VERSION 5.7 ;
  NOWIREEXTENSIONATPIN ON ;
  DIVIDERCHAR "/" ;
  BUSBITCHARS "[]" ;
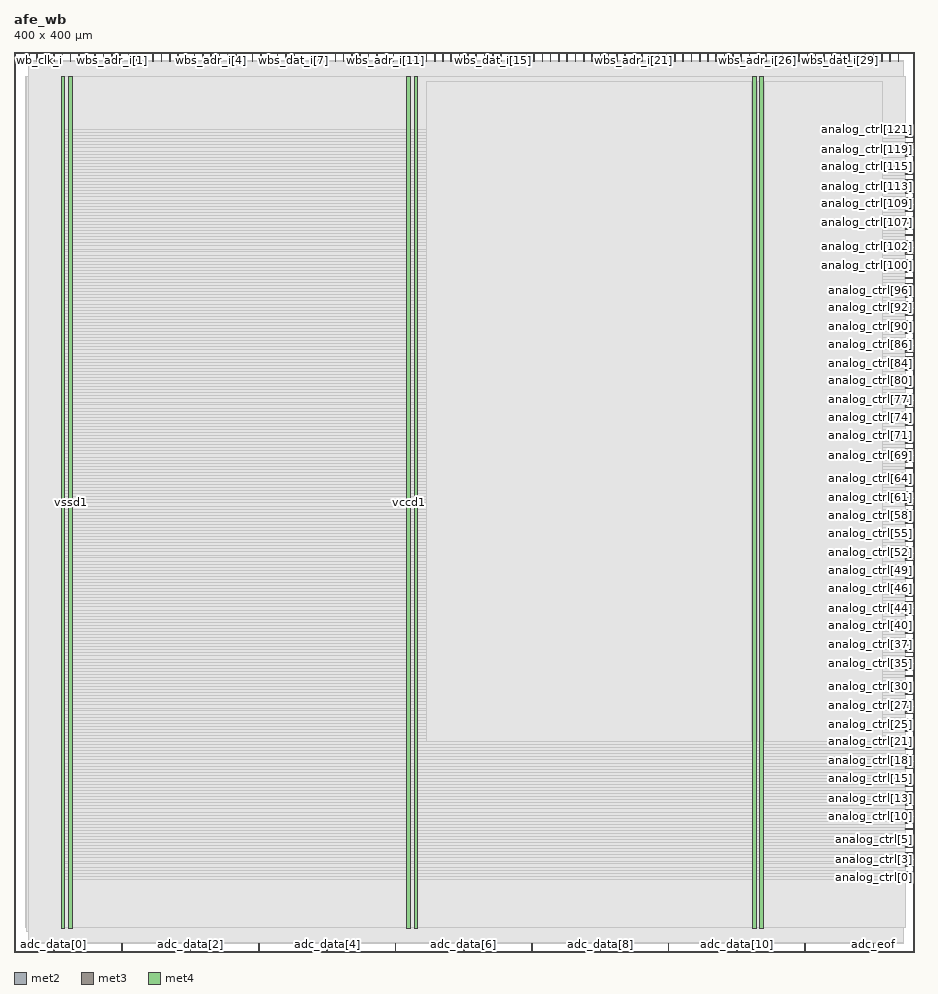
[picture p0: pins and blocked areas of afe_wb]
MACRO afe_wb
  CLASS BLOCK ;
  FOREIGN afe_wb ;
  ORIGIN 0.000 0.000 ;
  SIZE 400.000 BY 400.000 ;
  PIN adc_data[0]
    DIRECTION INPUT ;
    USE SIGNAL ;
    ANTENNAGATEAREA 0.213000 ;
    PORT
      LAYER met2 ;
        RECT 17.570 0.000 17.850 4.000 ;
    END
  END adc_data[0]
  PIN adc_data[10]
    DIRECTION INPUT ;
    USE SIGNAL ;
    ANTENNAGATEAREA 0.196500 ;
    PORT
      LAYER met2 ;
        RECT 321.170 0.000 321.450 4.000 ;
    END
  END adc_data[10]
  PIN adc_data[11]
    DIRECTION INPUT ;
    USE SIGNAL ;
    ANTENNAGATEAREA 0.126000 ;
    PORT
      LAYER met2 ;
        RECT 351.530 0.000 351.810 4.000 ;
    END
  END adc_data[11]
  PIN adc_data[1]
    DIRECTION INPUT ;
    USE SIGNAL ;
    ANTENNAGATEAREA 0.159000 ;
    PORT
      LAYER met2 ;
        RECT 47.930 0.000 48.210 4.000 ;
    END
  END adc_data[1]
  PIN adc_data[2]
    DIRECTION INPUT ;
    USE SIGNAL ;
    ANTENNAGATEAREA 0.213000 ;
    PORT
      LAYER met2 ;
        RECT 78.290 0.000 78.570 4.000 ;
    END
  END adc_data[2]
  PIN adc_data[3]
    DIRECTION INPUT ;
    USE SIGNAL ;
    ANTENNAGATEAREA 0.213000 ;
    PORT
      LAYER met2 ;
        RECT 108.650 0.000 108.930 4.000 ;
    END
  END adc_data[3]
  PIN adc_data[4]
    DIRECTION INPUT ;
    USE SIGNAL ;
    ANTENNAGATEAREA 0.213000 ;
    PORT
      LAYER met2 ;
        RECT 139.010 0.000 139.290 4.000 ;
    END
  END adc_data[4]
  PIN adc_data[5]
    DIRECTION INPUT ;
    USE SIGNAL ;
    ANTENNAGATEAREA 0.213000 ;
    PORT
      LAYER met2 ;
        RECT 169.370 0.000 169.650 4.000 ;
    END
  END adc_data[5]
  PIN adc_data[6]
    DIRECTION INPUT ;
    USE SIGNAL ;
    ANTENNAGATEAREA 0.213000 ;
    PORT
      LAYER met2 ;
        RECT 199.730 0.000 200.010 4.000 ;
    END
  END adc_data[6]
  PIN adc_data[7]
    DIRECTION INPUT ;
    USE SIGNAL ;
    ANTENNAGATEAREA 0.196500 ;
    PORT
      LAYER met2 ;
        RECT 230.090 0.000 230.370 4.000 ;
    END
  END adc_data[7]
  PIN adc_data[8]
    DIRECTION INPUT ;
    USE SIGNAL ;
    ANTENNAGATEAREA 0.196500 ;
    PORT
      LAYER met2 ;
        RECT 260.450 0.000 260.730 4.000 ;
    END
  END adc_data[8]
  PIN adc_data[9]
    DIRECTION INPUT ;
    USE SIGNAL ;
    ANTENNAGATEAREA 0.126000 ;
    PORT
      LAYER met2 ;
        RECT 290.810 0.000 291.090 4.000 ;
    END
  END adc_data[9]
  PIN adc_eof
    DIRECTION INPUT ;
    USE SIGNAL ;
    ANTENNAGATEAREA 0.213000 ;
    PORT
      LAYER met2 ;
        RECT 381.890 0.000 382.170 4.000 ;
    END
  END adc_eof
  PIN analog_ctrl[0]
    DIRECTION OUTPUT ;
    USE SIGNAL ;
    ANTENNADIFFAREA 2.673000 ;
    PORT
      LAYER met3 ;
        RECT 396.000 32.680 400.000 33.280 ;
    END
  END analog_ctrl[0]
  PIN analog_ctrl[100]
    DIRECTION OUTPUT ;
    USE SIGNAL ;
    PORT
      LAYER met3 ;
        RECT 396.000 304.680 400.000 305.280 ;
    END
  END analog_ctrl[100]
  PIN analog_ctrl[101]
    DIRECTION OUTPUT ;
    USE SIGNAL ;
    PORT
      LAYER met3 ;
        RECT 396.000 307.400 400.000 308.000 ;
    END
  END analog_ctrl[101]
  PIN analog_ctrl[102]
    DIRECTION OUTPUT ;
    USE SIGNAL ;
    PORT
      LAYER met3 ;
        RECT 396.000 310.120 400.000 310.720 ;
    END
  END analog_ctrl[102]
  PIN analog_ctrl[103]
    DIRECTION OUTPUT ;
    USE SIGNAL ;
    PORT
      LAYER met3 ;
        RECT 396.000 312.840 400.000 313.440 ;
    END
  END analog_ctrl[103]
  PIN analog_ctrl[104]
    DIRECTION OUTPUT ;
    USE SIGNAL ;
    ANTENNADIFFAREA 2.673000 ;
    PORT
      LAYER met3 ;
        RECT 396.000 315.560 400.000 316.160 ;
    END
  END analog_ctrl[104]
  PIN analog_ctrl[105]
    DIRECTION OUTPUT ;
    USE SIGNAL ;
    ANTENNADIFFAREA 2.673000 ;
    PORT
      LAYER met3 ;
        RECT 396.000 318.280 400.000 318.880 ;
    END
  END analog_ctrl[105]
  PIN analog_ctrl[106]
    DIRECTION OUTPUT ;
    USE SIGNAL ;
    ANTENNADIFFAREA 2.673000 ;
    PORT
      LAYER met3 ;
        RECT 396.000 321.000 400.000 321.600 ;
    END
  END analog_ctrl[106]
  PIN analog_ctrl[107]
    DIRECTION OUTPUT ;
    USE SIGNAL ;
    ANTENNADIFFAREA 2.673000 ;
    PORT
      LAYER met3 ;
        RECT 396.000 323.720 400.000 324.320 ;
    END
  END analog_ctrl[107]
  PIN analog_ctrl[108]
    DIRECTION OUTPUT ;
    USE SIGNAL ;
    ANTENNADIFFAREA 2.673000 ;
    PORT
      LAYER met3 ;
        RECT 396.000 326.440 400.000 327.040 ;
    END
  END analog_ctrl[108]
  PIN analog_ctrl[109]
    DIRECTION OUTPUT ;
    USE SIGNAL ;
    ANTENNADIFFAREA 2.673000 ;
    PORT
      LAYER met3 ;
        RECT 396.000 329.160 400.000 329.760 ;
    END
  END analog_ctrl[109]
  PIN analog_ctrl[10]
    DIRECTION OUTPUT ;
    USE SIGNAL ;
    ANTENNADIFFAREA 2.673000 ;
    PORT
      LAYER met3 ;
        RECT 396.000 59.880 400.000 60.480 ;
    END
  END analog_ctrl[10]
  PIN analog_ctrl[110]
    DIRECTION OUTPUT ;
    USE SIGNAL ;
    ANTENNADIFFAREA 2.673000 ;
    PORT
      LAYER met3 ;
        RECT 396.000 331.880 400.000 332.480 ;
    END
  END analog_ctrl[110]
  PIN analog_ctrl[111]
    DIRECTION OUTPUT ;
    USE SIGNAL ;
    ANTENNADIFFAREA 2.673000 ;
    PORT
      LAYER met3 ;
        RECT 396.000 334.600 400.000 335.200 ;
    END
  END analog_ctrl[111]
  PIN analog_ctrl[112]
    DIRECTION OUTPUT ;
    USE SIGNAL ;
    ANTENNADIFFAREA 2.673000 ;
    PORT
      LAYER met3 ;
        RECT 396.000 337.320 400.000 337.920 ;
    END
  END analog_ctrl[112]
  PIN analog_ctrl[113]
    DIRECTION OUTPUT ;
    USE SIGNAL ;
    ANTENNADIFFAREA 2.673000 ;
    PORT
      LAYER met3 ;
        RECT 396.000 340.040 400.000 340.640 ;
    END
  END analog_ctrl[113]
  PIN analog_ctrl[114]
    DIRECTION OUTPUT ;
    USE SIGNAL ;
    ANTENNADIFFAREA 2.673000 ;
    PORT
      LAYER met3 ;
        RECT 396.000 342.760 400.000 343.360 ;
    END
  END analog_ctrl[114]
  PIN analog_ctrl[115]
    DIRECTION OUTPUT ;
    USE SIGNAL ;
    ANTENNADIFFAREA 2.673000 ;
    PORT
      LAYER met3 ;
        RECT 396.000 345.480 400.000 346.080 ;
    END
  END analog_ctrl[115]
  PIN analog_ctrl[116]
    DIRECTION OUTPUT ;
    USE SIGNAL ;
    ANTENNADIFFAREA 2.673000 ;
    PORT
      LAYER met3 ;
        RECT 396.000 348.200 400.000 348.800 ;
    END
  END analog_ctrl[116]
  PIN analog_ctrl[117]
    DIRECTION OUTPUT ;
    USE SIGNAL ;
    ANTENNADIFFAREA 2.673000 ;
    PORT
      LAYER met3 ;
        RECT 396.000 350.920 400.000 351.520 ;
    END
  END analog_ctrl[117]
  PIN analog_ctrl[118]
    DIRECTION OUTPUT ;
    USE SIGNAL ;
    ANTENNADIFFAREA 2.673000 ;
    PORT
      LAYER met3 ;
        RECT 396.000 353.640 400.000 354.240 ;
    END
  END analog_ctrl[118]
  PIN analog_ctrl[119]
    DIRECTION OUTPUT ;
    USE SIGNAL ;
    ANTENNADIFFAREA 2.673000 ;
    PORT
      LAYER met3 ;
        RECT 396.000 356.360 400.000 356.960 ;
    END
  END analog_ctrl[119]
  PIN analog_ctrl[11]
    DIRECTION OUTPUT ;
    USE SIGNAL ;
    ANTENNADIFFAREA 2.673000 ;
    PORT
      LAYER met3 ;
        RECT 396.000 62.600 400.000 63.200 ;
    END
  END analog_ctrl[11]
  PIN analog_ctrl[120]
    DIRECTION OUTPUT ;
    USE SIGNAL ;
    ANTENNADIFFAREA 2.673000 ;
    PORT
      LAYER met3 ;
        RECT 396.000 359.080 400.000 359.680 ;
    END
  END analog_ctrl[120]
  PIN analog_ctrl[121]
    DIRECTION OUTPUT ;
    USE SIGNAL ;
    ANTENNADIFFAREA 2.673000 ;
    PORT
      LAYER met3 ;
        RECT 396.000 361.800 400.000 362.400 ;
    END
  END analog_ctrl[121]
  PIN analog_ctrl[122]
    DIRECTION OUTPUT ;
    USE SIGNAL ;
    ANTENNADIFFAREA 2.673000 ;
    PORT
      LAYER met3 ;
        RECT 396.000 364.520 400.000 365.120 ;
    END
  END analog_ctrl[122]
  PIN analog_ctrl[12]
    DIRECTION OUTPUT ;
    USE SIGNAL ;
    ANTENNADIFFAREA 2.673000 ;
    PORT
      LAYER met3 ;
        RECT 396.000 65.320 400.000 65.920 ;
    END
  END analog_ctrl[12]
  PIN analog_ctrl[13]
    DIRECTION OUTPUT ;
    USE SIGNAL ;
    ANTENNADIFFAREA 2.673000 ;
    PORT
      LAYER met3 ;
        RECT 396.000 68.040 400.000 68.640 ;
    END
  END analog_ctrl[13]
  PIN analog_ctrl[14]
    DIRECTION OUTPUT ;
    USE SIGNAL ;
    ANTENNADIFFAREA 2.673000 ;
    PORT
      LAYER met3 ;
        RECT 396.000 70.760 400.000 71.360 ;
    END
  END analog_ctrl[14]
  PIN analog_ctrl[15]
    DIRECTION OUTPUT ;
    USE SIGNAL ;
    ANTENNADIFFAREA 2.673000 ;
    PORT
      LAYER met3 ;
        RECT 396.000 73.480 400.000 74.080 ;
    END
  END analog_ctrl[15]
  PIN analog_ctrl[16]
    DIRECTION OUTPUT ;
    USE SIGNAL ;
    ANTENNADIFFAREA 2.673000 ;
    PORT
      LAYER met3 ;
        RECT 396.000 76.200 400.000 76.800 ;
    END
  END analog_ctrl[16]
  PIN analog_ctrl[17]
    DIRECTION OUTPUT ;
    USE SIGNAL ;
    ANTENNADIFFAREA 2.673000 ;
    PORT
      LAYER met3 ;
        RECT 396.000 78.920 400.000 79.520 ;
    END
  END analog_ctrl[17]
  PIN analog_ctrl[18]
    DIRECTION OUTPUT ;
    USE SIGNAL ;
    ANTENNADIFFAREA 2.673000 ;
    PORT
      LAYER met3 ;
        RECT 396.000 81.640 400.000 82.240 ;
    END
  END analog_ctrl[18]
  PIN analog_ctrl[19]
    DIRECTION OUTPUT ;
    USE SIGNAL ;
    ANTENNADIFFAREA 2.673000 ;
    PORT
      LAYER met3 ;
        RECT 396.000 84.360 400.000 84.960 ;
    END
  END analog_ctrl[19]
  PIN analog_ctrl[1]
    DIRECTION OUTPUT ;
    USE SIGNAL ;
    ANTENNADIFFAREA 2.673000 ;
    PORT
      LAYER met3 ;
        RECT 396.000 35.400 400.000 36.000 ;
    END
  END analog_ctrl[1]
  PIN analog_ctrl[20]
    DIRECTION OUTPUT ;
    USE SIGNAL ;
    ANTENNADIFFAREA 2.673000 ;
    PORT
      LAYER met3 ;
        RECT 396.000 87.080 400.000 87.680 ;
    END
  END analog_ctrl[20]
  PIN analog_ctrl[21]
    DIRECTION OUTPUT ;
    USE SIGNAL ;
    ANTENNADIFFAREA 2.673000 ;
    PORT
      LAYER met3 ;
        RECT 396.000 89.800 400.000 90.400 ;
    END
  END analog_ctrl[21]
  PIN analog_ctrl[22]
    DIRECTION OUTPUT ;
    USE SIGNAL ;
    ANTENNADIFFAREA 2.673000 ;
    PORT
      LAYER met3 ;
        RECT 396.000 92.520 400.000 93.120 ;
    END
  END analog_ctrl[22]
  PIN analog_ctrl[23]
    DIRECTION OUTPUT ;
    USE SIGNAL ;
    ANTENNADIFFAREA 2.673000 ;
    PORT
      LAYER met3 ;
        RECT 396.000 95.240 400.000 95.840 ;
    END
  END analog_ctrl[23]
  PIN analog_ctrl[24]
    DIRECTION OUTPUT ;
    USE SIGNAL ;
    ANTENNADIFFAREA 2.673000 ;
    PORT
      LAYER met3 ;
        RECT 396.000 97.960 400.000 98.560 ;
    END
  END analog_ctrl[24]
  PIN analog_ctrl[25]
    DIRECTION OUTPUT ;
    USE SIGNAL ;
    ANTENNADIFFAREA 2.673000 ;
    PORT
      LAYER met3 ;
        RECT 396.000 100.680 400.000 101.280 ;
    END
  END analog_ctrl[25]
  PIN analog_ctrl[26]
    DIRECTION OUTPUT ;
    USE SIGNAL ;
    ANTENNADIFFAREA 2.673000 ;
    PORT
      LAYER met3 ;
        RECT 396.000 103.400 400.000 104.000 ;
    END
  END analog_ctrl[26]
  PIN analog_ctrl[27]
    DIRECTION OUTPUT ;
    USE SIGNAL ;
    ANTENNADIFFAREA 2.673000 ;
    PORT
      LAYER met3 ;
        RECT 396.000 106.120 400.000 106.720 ;
    END
  END analog_ctrl[27]
  PIN analog_ctrl[28]
    DIRECTION OUTPUT ;
    USE SIGNAL ;
    ANTENNADIFFAREA 2.673000 ;
    PORT
      LAYER met3 ;
        RECT 396.000 108.840 400.000 109.440 ;
    END
  END analog_ctrl[28]
  PIN analog_ctrl[29]
    DIRECTION OUTPUT ;
    USE SIGNAL ;
    ANTENNADIFFAREA 2.673000 ;
    PORT
      LAYER met3 ;
        RECT 396.000 111.560 400.000 112.160 ;
    END
  END analog_ctrl[29]
  PIN analog_ctrl[2]
    DIRECTION OUTPUT ;
    USE SIGNAL ;
    ANTENNADIFFAREA 2.673000 ;
    PORT
      LAYER met3 ;
        RECT 396.000 38.120 400.000 38.720 ;
    END
  END analog_ctrl[2]
  PIN analog_ctrl[30]
    DIRECTION OUTPUT ;
    USE SIGNAL ;
    ANTENNADIFFAREA 2.673000 ;
    PORT
      LAYER met3 ;
        RECT 396.000 114.280 400.000 114.880 ;
    END
  END analog_ctrl[30]
  PIN analog_ctrl[31]
    DIRECTION OUTPUT ;
    USE SIGNAL ;
    ANTENNADIFFAREA 2.673000 ;
    PORT
      LAYER met3 ;
        RECT 396.000 117.000 400.000 117.600 ;
    END
  END analog_ctrl[31]
  PIN analog_ctrl[32]
    DIRECTION OUTPUT ;
    USE SIGNAL ;
    ANTENNADIFFAREA 2.673000 ;
    PORT
      LAYER met3 ;
        RECT 396.000 119.720 400.000 120.320 ;
    END
  END analog_ctrl[32]
  PIN analog_ctrl[33]
    DIRECTION OUTPUT ;
    USE SIGNAL ;
    ANTENNADIFFAREA 2.673000 ;
    PORT
      LAYER met3 ;
        RECT 396.000 122.440 400.000 123.040 ;
    END
  END analog_ctrl[33]
  PIN analog_ctrl[34]
    DIRECTION OUTPUT ;
    USE SIGNAL ;
    ANTENNADIFFAREA 2.673000 ;
    PORT
      LAYER met3 ;
        RECT 396.000 125.160 400.000 125.760 ;
    END
  END analog_ctrl[34]
  PIN analog_ctrl[35]
    DIRECTION OUTPUT ;
    USE SIGNAL ;
    ANTENNADIFFAREA 2.673000 ;
    PORT
      LAYER met3 ;
        RECT 396.000 127.880 400.000 128.480 ;
    END
  END analog_ctrl[35]
  PIN analog_ctrl[36]
    DIRECTION OUTPUT ;
    USE SIGNAL ;
    ANTENNADIFFAREA 2.673000 ;
    PORT
      LAYER met3 ;
        RECT 396.000 130.600 400.000 131.200 ;
    END
  END analog_ctrl[36]
  PIN analog_ctrl[37]
    DIRECTION OUTPUT ;
    USE SIGNAL ;
    ANTENNADIFFAREA 2.673000 ;
    PORT
      LAYER met3 ;
        RECT 396.000 133.320 400.000 133.920 ;
    END
  END analog_ctrl[37]
  PIN analog_ctrl[38]
    DIRECTION OUTPUT ;
    USE SIGNAL ;
    ANTENNADIFFAREA 2.673000 ;
    PORT
      LAYER met3 ;
        RECT 396.000 136.040 400.000 136.640 ;
    END
  END analog_ctrl[38]
  PIN analog_ctrl[39]
    DIRECTION OUTPUT ;
    USE SIGNAL ;
    ANTENNADIFFAREA 2.673000 ;
    PORT
      LAYER met3 ;
        RECT 396.000 138.760 400.000 139.360 ;
    END
  END analog_ctrl[39]
  PIN analog_ctrl[3]
    DIRECTION OUTPUT ;
    USE SIGNAL ;
    ANTENNADIFFAREA 2.673000 ;
    PORT
      LAYER met3 ;
        RECT 396.000 40.840 400.000 41.440 ;
    END
  END analog_ctrl[3]
  PIN analog_ctrl[40]
    DIRECTION OUTPUT ;
    USE SIGNAL ;
    ANTENNADIFFAREA 2.673000 ;
    PORT
      LAYER met3 ;
        RECT 396.000 141.480 400.000 142.080 ;
    END
  END analog_ctrl[40]
  PIN analog_ctrl[41]
    DIRECTION OUTPUT ;
    USE SIGNAL ;
    ANTENNADIFFAREA 2.673000 ;
    PORT
      LAYER met3 ;
        RECT 396.000 144.200 400.000 144.800 ;
    END
  END analog_ctrl[41]
  PIN analog_ctrl[42]
    DIRECTION OUTPUT ;
    USE SIGNAL ;
    ANTENNADIFFAREA 2.673000 ;
    PORT
      LAYER met3 ;
        RECT 396.000 146.920 400.000 147.520 ;
    END
  END analog_ctrl[42]
  PIN analog_ctrl[43]
    DIRECTION OUTPUT ;
    USE SIGNAL ;
    ANTENNADIFFAREA 2.673000 ;
    PORT
      LAYER met3 ;
        RECT 396.000 149.640 400.000 150.240 ;
    END
  END analog_ctrl[43]
  PIN analog_ctrl[44]
    DIRECTION OUTPUT ;
    USE SIGNAL ;
    ANTENNADIFFAREA 2.673000 ;
    PORT
      LAYER met3 ;
        RECT 396.000 152.360 400.000 152.960 ;
    END
  END analog_ctrl[44]
  PIN analog_ctrl[45]
    DIRECTION OUTPUT ;
    USE SIGNAL ;
    ANTENNADIFFAREA 2.673000 ;
    PORT
      LAYER met3 ;
        RECT 396.000 155.080 400.000 155.680 ;
    END
  END analog_ctrl[45]
  PIN analog_ctrl[46]
    DIRECTION OUTPUT ;
    USE SIGNAL ;
    ANTENNADIFFAREA 2.673000 ;
    PORT
      LAYER met3 ;
        RECT 396.000 157.800 400.000 158.400 ;
    END
  END analog_ctrl[46]
  PIN analog_ctrl[47]
    DIRECTION OUTPUT ;
    USE SIGNAL ;
    ANTENNADIFFAREA 2.673000 ;
    PORT
      LAYER met3 ;
        RECT 396.000 160.520 400.000 161.120 ;
    END
  END analog_ctrl[47]
  PIN analog_ctrl[48]
    DIRECTION OUTPUT ;
    USE SIGNAL ;
    ANTENNADIFFAREA 2.673000 ;
    PORT
      LAYER met3 ;
        RECT 396.000 163.240 400.000 163.840 ;
    END
  END analog_ctrl[48]
  PIN analog_ctrl[49]
    DIRECTION OUTPUT ;
    USE SIGNAL ;
    ANTENNADIFFAREA 2.673000 ;
    PORT
      LAYER met3 ;
        RECT 396.000 165.960 400.000 166.560 ;
    END
  END analog_ctrl[49]
  PIN analog_ctrl[4]
    DIRECTION OUTPUT ;
    USE SIGNAL ;
    ANTENNADIFFAREA 2.673000 ;
    PORT
      LAYER met3 ;
        RECT 396.000 43.560 400.000 44.160 ;
    END
  END analog_ctrl[4]
  PIN analog_ctrl[50]
    DIRECTION OUTPUT ;
    USE SIGNAL ;
    ANTENNADIFFAREA 2.673000 ;
    PORT
      LAYER met3 ;
        RECT 396.000 168.680 400.000 169.280 ;
    END
  END analog_ctrl[50]
  PIN analog_ctrl[51]
    DIRECTION OUTPUT ;
    USE SIGNAL ;
    ANTENNADIFFAREA 2.673000 ;
    PORT
      LAYER met3 ;
        RECT 396.000 171.400 400.000 172.000 ;
    END
  END analog_ctrl[51]
  PIN analog_ctrl[52]
    DIRECTION OUTPUT ;
    USE SIGNAL ;
    ANTENNADIFFAREA 2.673000 ;
    PORT
      LAYER met3 ;
        RECT 396.000 174.120 400.000 174.720 ;
    END
  END analog_ctrl[52]
  PIN analog_ctrl[53]
    DIRECTION OUTPUT ;
    USE SIGNAL ;
    ANTENNADIFFAREA 2.673000 ;
    PORT
      LAYER met3 ;
        RECT 396.000 176.840 400.000 177.440 ;
    END
  END analog_ctrl[53]
  PIN analog_ctrl[54]
    DIRECTION OUTPUT ;
    USE SIGNAL ;
    ANTENNADIFFAREA 2.673000 ;
    PORT
      LAYER met3 ;
        RECT 396.000 179.560 400.000 180.160 ;
    END
  END analog_ctrl[54]
  PIN analog_ctrl[55]
    DIRECTION OUTPUT ;
    USE SIGNAL ;
    ANTENNADIFFAREA 2.673000 ;
    PORT
      LAYER met3 ;
        RECT 396.000 182.280 400.000 182.880 ;
    END
  END analog_ctrl[55]
  PIN analog_ctrl[56]
    DIRECTION OUTPUT ;
    USE SIGNAL ;
    ANTENNADIFFAREA 2.673000 ;
    PORT
      LAYER met3 ;
        RECT 396.000 185.000 400.000 185.600 ;
    END
  END analog_ctrl[56]
  PIN analog_ctrl[57]
    DIRECTION OUTPUT ;
    USE SIGNAL ;
    ANTENNADIFFAREA 2.673000 ;
    PORT
      LAYER met3 ;
        RECT 396.000 187.720 400.000 188.320 ;
    END
  END analog_ctrl[57]
  PIN analog_ctrl[58]
    DIRECTION OUTPUT ;
    USE SIGNAL ;
    ANTENNADIFFAREA 2.673000 ;
    PORT
      LAYER met3 ;
        RECT 396.000 190.440 400.000 191.040 ;
    END
  END analog_ctrl[58]
  PIN analog_ctrl[59]
    DIRECTION OUTPUT ;
    USE SIGNAL ;
    ANTENNADIFFAREA 2.673000 ;
    PORT
      LAYER met3 ;
        RECT 396.000 193.160 400.000 193.760 ;
    END
  END analog_ctrl[59]
  PIN analog_ctrl[5]
    DIRECTION OUTPUT ;
    USE SIGNAL ;
    ANTENNADIFFAREA 2.673000 ;
    PORT
      LAYER met3 ;
        RECT 396.000 46.280 400.000 46.880 ;
    END
  END analog_ctrl[5]
  PIN analog_ctrl[60]
    DIRECTION OUTPUT ;
    USE SIGNAL ;
    ANTENNADIFFAREA 2.673000 ;
    PORT
      LAYER met3 ;
        RECT 396.000 195.880 400.000 196.480 ;
    END
  END analog_ctrl[60]
  PIN analog_ctrl[61]
    DIRECTION OUTPUT ;
    USE SIGNAL ;
    ANTENNADIFFAREA 2.673000 ;
    PORT
      LAYER met3 ;
        RECT 396.000 198.600 400.000 199.200 ;
    END
  END analog_ctrl[61]
  PIN analog_ctrl[62]
    DIRECTION OUTPUT ;
    USE SIGNAL ;
    ANTENNADIFFAREA 2.673000 ;
    PORT
      LAYER met3 ;
        RECT 396.000 201.320 400.000 201.920 ;
    END
  END analog_ctrl[62]
  PIN analog_ctrl[63]
    DIRECTION OUTPUT ;
    USE SIGNAL ;
    ANTENNADIFFAREA 2.673000 ;
    PORT
      LAYER met3 ;
        RECT 396.000 204.040 400.000 204.640 ;
    END
  END analog_ctrl[63]
  PIN analog_ctrl[64]
    DIRECTION OUTPUT ;
    USE SIGNAL ;
    ANTENNADIFFAREA 2.673000 ;
    PORT
      LAYER met3 ;
        RECT 396.000 206.760 400.000 207.360 ;
    END
  END analog_ctrl[64]
  PIN analog_ctrl[65]
    DIRECTION OUTPUT ;
    USE SIGNAL ;
    ANTENNADIFFAREA 2.673000 ;
    PORT
      LAYER met3 ;
        RECT 396.000 209.480 400.000 210.080 ;
    END
  END analog_ctrl[65]
  PIN analog_ctrl[66]
    DIRECTION OUTPUT ;
    USE SIGNAL ;
    ANTENNADIFFAREA 2.673000 ;
    PORT
      LAYER met3 ;
        RECT 396.000 212.200 400.000 212.800 ;
    END
  END analog_ctrl[66]
  PIN analog_ctrl[67]
    DIRECTION OUTPUT ;
    USE SIGNAL ;
    ANTENNADIFFAREA 2.673000 ;
    PORT
      LAYER met3 ;
        RECT 396.000 214.920 400.000 215.520 ;
    END
  END analog_ctrl[67]
  PIN analog_ctrl[68]
    DIRECTION OUTPUT ;
    USE SIGNAL ;
    ANTENNADIFFAREA 2.673000 ;
    PORT
      LAYER met3 ;
        RECT 396.000 217.640 400.000 218.240 ;
    END
  END analog_ctrl[68]
  PIN analog_ctrl[69]
    DIRECTION OUTPUT ;
    USE SIGNAL ;
    ANTENNADIFFAREA 2.673000 ;
    PORT
      LAYER met3 ;
        RECT 396.000 220.360 400.000 220.960 ;
    END
  END analog_ctrl[69]
  PIN analog_ctrl[6]
    DIRECTION OUTPUT ;
    USE SIGNAL ;
    ANTENNADIFFAREA 2.673000 ;
    PORT
      LAYER met3 ;
        RECT 396.000 49.000 400.000 49.600 ;
    END
  END analog_ctrl[6]
  PIN analog_ctrl[70]
    DIRECTION OUTPUT ;
    USE SIGNAL ;
    ANTENNADIFFAREA 2.673000 ;
    PORT
      LAYER met3 ;
        RECT 396.000 223.080 400.000 223.680 ;
    END
  END analog_ctrl[70]
  PIN analog_ctrl[71]
    DIRECTION OUTPUT ;
    USE SIGNAL ;
    ANTENNADIFFAREA 2.673000 ;
    PORT
      LAYER met3 ;
        RECT 396.000 225.800 400.000 226.400 ;
    END
  END analog_ctrl[71]
  PIN analog_ctrl[72]
    DIRECTION OUTPUT ;
    USE SIGNAL ;
    ANTENNADIFFAREA 2.673000 ;
    PORT
      LAYER met3 ;
        RECT 396.000 228.520 400.000 229.120 ;
    END
  END analog_ctrl[72]
  PIN analog_ctrl[73]
    DIRECTION OUTPUT ;
    USE SIGNAL ;
    ANTENNADIFFAREA 2.673000 ;
    PORT
      LAYER met3 ;
        RECT 396.000 231.240 400.000 231.840 ;
    END
  END analog_ctrl[73]
  PIN analog_ctrl[74]
    DIRECTION OUTPUT ;
    USE SIGNAL ;
    ANTENNADIFFAREA 2.673000 ;
    PORT
      LAYER met3 ;
        RECT 396.000 233.960 400.000 234.560 ;
    END
  END analog_ctrl[74]
  PIN analog_ctrl[75]
    DIRECTION OUTPUT ;
    USE SIGNAL ;
    ANTENNADIFFAREA 2.673000 ;
    PORT
      LAYER met3 ;
        RECT 396.000 236.680 400.000 237.280 ;
    END
  END analog_ctrl[75]
  PIN analog_ctrl[76]
    DIRECTION OUTPUT ;
    USE SIGNAL ;
    ANTENNADIFFAREA 2.673000 ;
    PORT
      LAYER met3 ;
        RECT 396.000 239.400 400.000 240.000 ;
    END
  END analog_ctrl[76]
  PIN analog_ctrl[77]
    DIRECTION OUTPUT ;
    USE SIGNAL ;
    ANTENNADIFFAREA 2.673000 ;
    PORT
      LAYER met3 ;
        RECT 396.000 242.120 400.000 242.720 ;
    END
  END analog_ctrl[77]
  PIN analog_ctrl[78]
    DIRECTION OUTPUT ;
    USE SIGNAL ;
    ANTENNADIFFAREA 2.673000 ;
    PORT
      LAYER met3 ;
        RECT 396.000 244.840 400.000 245.440 ;
    END
  END analog_ctrl[78]
  PIN analog_ctrl[79]
    DIRECTION OUTPUT ;
    USE SIGNAL ;
    ANTENNADIFFAREA 2.673000 ;
    PORT
      LAYER met3 ;
        RECT 396.000 247.560 400.000 248.160 ;
    END
  END analog_ctrl[79]
  PIN analog_ctrl[7]
    DIRECTION OUTPUT ;
    USE SIGNAL ;
    PORT
      LAYER met3 ;
        RECT 396.000 51.720 400.000 52.320 ;
    END
  END analog_ctrl[7]
  PIN analog_ctrl[80]
    DIRECTION OUTPUT ;
    USE SIGNAL ;
    ANTENNADIFFAREA 2.673000 ;
    PORT
      LAYER met3 ;
        RECT 396.000 250.280 400.000 250.880 ;
    END
  END analog_ctrl[80]
  PIN analog_ctrl[81]
    DIRECTION OUTPUT ;
    USE SIGNAL ;
    ANTENNADIFFAREA 2.673000 ;
    PORT
      LAYER met3 ;
        RECT 396.000 253.000 400.000 253.600 ;
    END
  END analog_ctrl[81]
  PIN analog_ctrl[82]
    DIRECTION OUTPUT ;
    USE SIGNAL ;
    ANTENNADIFFAREA 2.673000 ;
    PORT
      LAYER met3 ;
        RECT 396.000 255.720 400.000 256.320 ;
    END
  END analog_ctrl[82]
  PIN analog_ctrl[83]
    DIRECTION OUTPUT ;
    USE SIGNAL ;
    ANTENNADIFFAREA 2.673000 ;
    PORT
      LAYER met3 ;
        RECT 396.000 258.440 400.000 259.040 ;
    END
  END analog_ctrl[83]
  PIN analog_ctrl[84]
    DIRECTION OUTPUT ;
    USE SIGNAL ;
    ANTENNADIFFAREA 2.673000 ;
    PORT
      LAYER met3 ;
        RECT 396.000 261.160 400.000 261.760 ;
    END
  END analog_ctrl[84]
  PIN analog_ctrl[85]
    DIRECTION OUTPUT ;
    USE SIGNAL ;
    ANTENNADIFFAREA 2.673000 ;
    PORT
      LAYER met3 ;
        RECT 396.000 263.880 400.000 264.480 ;
    END
  END analog_ctrl[85]
  PIN analog_ctrl[86]
    DIRECTION OUTPUT ;
    USE SIGNAL ;
    ANTENNADIFFAREA 2.673000 ;
    PORT
      LAYER met3 ;
        RECT 396.000 266.600 400.000 267.200 ;
    END
  END analog_ctrl[86]
  PIN analog_ctrl[87]
    DIRECTION OUTPUT ;
    USE SIGNAL ;
    ANTENNADIFFAREA 2.673000 ;
    PORT
      LAYER met3 ;
        RECT 396.000 269.320 400.000 269.920 ;
    END
  END analog_ctrl[87]
  PIN analog_ctrl[88]
    DIRECTION OUTPUT ;
    USE SIGNAL ;
    ANTENNADIFFAREA 2.673000 ;
    PORT
      LAYER met3 ;
        RECT 396.000 272.040 400.000 272.640 ;
    END
  END analog_ctrl[88]
  PIN analog_ctrl[89]
    DIRECTION OUTPUT ;
    USE SIGNAL ;
    ANTENNADIFFAREA 2.673000 ;
    PORT
      LAYER met3 ;
        RECT 396.000 274.760 400.000 275.360 ;
    END
  END analog_ctrl[89]
  PIN analog_ctrl[8]
    DIRECTION OUTPUT ;
    USE SIGNAL ;
    ANTENNADIFFAREA 2.673000 ;
    PORT
      LAYER met3 ;
        RECT 396.000 54.440 400.000 55.040 ;
    END
  END analog_ctrl[8]
  PIN analog_ctrl[90]
    DIRECTION OUTPUT ;
    USE SIGNAL ;
    ANTENNADIFFAREA 2.673000 ;
    PORT
      LAYER met3 ;
        RECT 396.000 277.480 400.000 278.080 ;
    END
  END analog_ctrl[90]
  PIN analog_ctrl[91]
    DIRECTION OUTPUT ;
    USE SIGNAL ;
    ANTENNADIFFAREA 2.673000 ;
    PORT
      LAYER met3 ;
        RECT 396.000 280.200 400.000 280.800 ;
    END
  END analog_ctrl[91]
  PIN analog_ctrl[92]
    DIRECTION OUTPUT ;
    USE SIGNAL ;
    ANTENNADIFFAREA 2.673000 ;
    PORT
      LAYER met3 ;
        RECT 396.000 282.920 400.000 283.520 ;
    END
  END analog_ctrl[92]
  PIN analog_ctrl[93]
    DIRECTION OUTPUT ;
    USE SIGNAL ;
    ANTENNADIFFAREA 2.673000 ;
    PORT
      LAYER met3 ;
        RECT 396.000 285.640 400.000 286.240 ;
    END
  END analog_ctrl[93]
  PIN analog_ctrl[94]
    DIRECTION OUTPUT ;
    USE SIGNAL ;
    ANTENNADIFFAREA 2.673000 ;
    PORT
      LAYER met3 ;
        RECT 396.000 288.360 400.000 288.960 ;
    END
  END analog_ctrl[94]
  PIN analog_ctrl[95]
    DIRECTION OUTPUT ;
    USE SIGNAL ;
    ANTENNADIFFAREA 2.673000 ;
    PORT
      LAYER met3 ;
        RECT 396.000 291.080 400.000 291.680 ;
    END
  END analog_ctrl[95]
  PIN analog_ctrl[96]
    DIRECTION OUTPUT ;
    USE SIGNAL ;
    ANTENNADIFFAREA 2.673000 ;
    PORT
      LAYER met3 ;
        RECT 396.000 293.800 400.000 294.400 ;
    END
  END analog_ctrl[96]
  PIN analog_ctrl[97]
    DIRECTION OUTPUT ;
    USE SIGNAL ;
    ANTENNADIFFAREA 2.673000 ;
    PORT
      LAYER met3 ;
        RECT 396.000 296.520 400.000 297.120 ;
    END
  END analog_ctrl[97]
  PIN analog_ctrl[98]
    DIRECTION OUTPUT ;
    USE SIGNAL ;
    PORT
      LAYER met3 ;
        RECT 396.000 299.240 400.000 299.840 ;
    END
  END analog_ctrl[98]
  PIN analog_ctrl[99]
    DIRECTION OUTPUT ;
    USE SIGNAL ;
    PORT
      LAYER met3 ;
        RECT 396.000 301.960 400.000 302.560 ;
    END
  END analog_ctrl[99]
  PIN analog_ctrl[9]
    DIRECTION OUTPUT ;
    USE SIGNAL ;
    ANTENNADIFFAREA 2.673000 ;
    PORT
      LAYER met3 ;
        RECT 396.000 57.160 400.000 57.760 ;
    END
  END analog_ctrl[9]
  PIN vccd1
    DIRECTION INOUT ;
    USE POWER ;
    PORT
      LAYER met4 ;
        RECT 21.040 10.640 22.640 389.200 ;
    END
    PORT
      LAYER met4 ;
        RECT 174.640 10.640 176.240 389.200 ;
    END
    PORT
      LAYER met4 ;
        RECT 328.240 10.640 329.840 389.200 ;
    END
  END vccd1
  PIN vssd1
    DIRECTION INOUT ;
    USE GROUND ;
    PORT
      LAYER met4 ;
        RECT 24.340 10.640 25.940 389.200 ;
    END
    PORT
      LAYER met4 ;
        RECT 177.940 10.640 179.540 389.200 ;
    END
    PORT
      LAYER met4 ;
        RECT 331.540 10.640 333.140 389.200 ;
    END
  END vssd1
  PIN wb_clk_i
    DIRECTION INPUT ;
    USE SIGNAL ;
    ANTENNAGATEAREA 0.852000 ;
    PORT
      LAYER met2 ;
        RECT 6.530 396.000 6.810 400.000 ;
    END
  END wb_clk_i
  PIN wb_rst_i
    DIRECTION INPUT ;
    USE SIGNAL ;
    ANTENNAGATEAREA 0.126000 ;
    PORT
      LAYER met2 ;
        RECT 10.210 396.000 10.490 400.000 ;
    END
  END wb_rst_i
  PIN wbs_ack_o
    DIRECTION OUTPUT ;
    USE SIGNAL ;
    ANTENNADIFFAREA 2.673000 ;
    PORT
      LAYER met2 ;
        RECT 13.890 396.000 14.170 400.000 ;
    END
  END wbs_ack_o
  PIN wbs_adr_i[0]
    DIRECTION INPUT ;
    USE SIGNAL ;
    PORT
      LAYER met2 ;
        RECT 28.610 396.000 28.890 400.000 ;
    END
  END wbs_adr_i[0]
  PIN wbs_adr_i[10]
    DIRECTION INPUT ;
    USE SIGNAL ;
    PORT
      LAYER met2 ;
        RECT 153.730 396.000 154.010 400.000 ;
    END
  END wbs_adr_i[10]
  PIN wbs_adr_i[11]
    DIRECTION INPUT ;
    USE SIGNAL ;
    PORT
      LAYER met2 ;
        RECT 164.770 396.000 165.050 400.000 ;
    END
  END wbs_adr_i[11]
  PIN wbs_adr_i[12]
    DIRECTION INPUT ;
    USE SIGNAL ;
    PORT
      LAYER met2 ;
        RECT 175.810 396.000 176.090 400.000 ;
    END
  END wbs_adr_i[12]
  PIN wbs_adr_i[13]
    DIRECTION INPUT ;
    USE SIGNAL ;
    PORT
      LAYER met2 ;
        RECT 186.850 396.000 187.130 400.000 ;
    END
  END wbs_adr_i[13]
  PIN wbs_adr_i[14]
    DIRECTION INPUT ;
    USE SIGNAL ;
    PORT
      LAYER met2 ;
        RECT 197.890 396.000 198.170 400.000 ;
    END
  END wbs_adr_i[14]
  PIN wbs_adr_i[15]
    DIRECTION INPUT ;
    USE SIGNAL ;
    PORT
      LAYER met2 ;
        RECT 208.930 396.000 209.210 400.000 ;
    END
  END wbs_adr_i[15]
  PIN wbs_adr_i[16]
    DIRECTION INPUT ;
    USE SIGNAL ;
    PORT
      LAYER met2 ;
        RECT 219.970 396.000 220.250 400.000 ;
    END
  END wbs_adr_i[16]
  PIN wbs_adr_i[17]
    DIRECTION INPUT ;
    USE SIGNAL ;
    PORT
      LAYER met2 ;
        RECT 231.010 396.000 231.290 400.000 ;
    END
  END wbs_adr_i[17]
  PIN wbs_adr_i[18]
    DIRECTION INPUT ;
    USE SIGNAL ;
    PORT
      LAYER met2 ;
        RECT 242.050 396.000 242.330 400.000 ;
    END
  END wbs_adr_i[18]
  PIN wbs_adr_i[19]
    DIRECTION INPUT ;
    USE SIGNAL ;
    PORT
      LAYER met2 ;
        RECT 253.090 396.000 253.370 400.000 ;
    END
  END wbs_adr_i[19]
  PIN wbs_adr_i[1]
    DIRECTION INPUT ;
    USE SIGNAL ;
    PORT
      LAYER met2 ;
        RECT 43.330 396.000 43.610 400.000 ;
    END
  END wbs_adr_i[1]
  PIN wbs_adr_i[20]
    DIRECTION INPUT ;
    USE SIGNAL ;
    PORT
      LAYER met2 ;
        RECT 264.130 396.000 264.410 400.000 ;
    END
  END wbs_adr_i[20]
  PIN wbs_adr_i[21]
    DIRECTION INPUT ;
    USE SIGNAL ;
    PORT
      LAYER met2 ;
        RECT 275.170 396.000 275.450 400.000 ;
    END
  END wbs_adr_i[21]
  PIN wbs_adr_i[22]
    DIRECTION INPUT ;
    USE SIGNAL ;
    PORT
      LAYER met2 ;
        RECT 286.210 396.000 286.490 400.000 ;
    END
  END wbs_adr_i[22]
  PIN wbs_adr_i[23]
    DIRECTION INPUT ;
    USE SIGNAL ;
    PORT
      LAYER met2 ;
        RECT 297.250 396.000 297.530 400.000 ;
    END
  END wbs_adr_i[23]
  PIN wbs_adr_i[24]
    DIRECTION INPUT ;
    USE SIGNAL ;
    PORT
      LAYER met2 ;
        RECT 308.290 396.000 308.570 400.000 ;
    END
  END wbs_adr_i[24]
  PIN wbs_adr_i[25]
    DIRECTION INPUT ;
    USE SIGNAL ;
    PORT
      LAYER met2 ;
        RECT 319.330 396.000 319.610 400.000 ;
    END
  END wbs_adr_i[25]
  PIN wbs_adr_i[26]
    DIRECTION INPUT ;
    USE SIGNAL ;
    PORT
      LAYER met2 ;
        RECT 330.370 396.000 330.650 400.000 ;
    END
  END wbs_adr_i[26]
  PIN wbs_adr_i[27]
    DIRECTION INPUT ;
    USE SIGNAL ;
    PORT
      LAYER met2 ;
        RECT 341.410 396.000 341.690 400.000 ;
    END
  END wbs_adr_i[27]
  PIN wbs_adr_i[28]
    DIRECTION INPUT ;
    USE SIGNAL ;
    PORT
      LAYER met2 ;
        RECT 352.450 396.000 352.730 400.000 ;
    END
  END wbs_adr_i[28]
  PIN wbs_adr_i[29]
    DIRECTION INPUT ;
    USE SIGNAL ;
    PORT
      LAYER met2 ;
        RECT 363.490 396.000 363.770 400.000 ;
    END
  END wbs_adr_i[29]
  PIN wbs_adr_i[2]
    DIRECTION INPUT ;
    USE SIGNAL ;
    ANTENNAGATEAREA 0.126000 ;
    PORT
      LAYER met2 ;
        RECT 58.050 396.000 58.330 400.000 ;
    END
  END wbs_adr_i[2]
  PIN wbs_adr_i[30]
    DIRECTION INPUT ;
    USE SIGNAL ;
    PORT
      LAYER met2 ;
        RECT 374.530 396.000 374.810 400.000 ;
    END
  END wbs_adr_i[30]
  PIN wbs_adr_i[31]
    DIRECTION INPUT ;
    USE SIGNAL ;
    PORT
      LAYER met2 ;
        RECT 385.570 396.000 385.850 400.000 ;
    END
  END wbs_adr_i[31]
  PIN wbs_adr_i[3]
    DIRECTION INPUT ;
    USE SIGNAL ;
    ANTENNAGATEAREA 0.126000 ;
    PORT
      LAYER met2 ;
        RECT 72.770 396.000 73.050 400.000 ;
    END
  END wbs_adr_i[3]
  PIN wbs_adr_i[4]
    DIRECTION INPUT ;
    USE SIGNAL ;
    ANTENNAGATEAREA 0.126000 ;
    PORT
      LAYER met2 ;
        RECT 87.490 396.000 87.770 400.000 ;
    END
  END wbs_adr_i[4]
  PIN wbs_adr_i[5]
    DIRECTION INPUT ;
    USE SIGNAL ;
    ANTENNAGATEAREA 0.126000 ;
    PORT
      LAYER met2 ;
        RECT 98.530 396.000 98.810 400.000 ;
    END
  END wbs_adr_i[5]
  PIN wbs_adr_i[6]
    DIRECTION INPUT ;
    USE SIGNAL ;
    PORT
      LAYER met2 ;
        RECT 109.570 396.000 109.850 400.000 ;
    END
  END wbs_adr_i[6]
  PIN wbs_adr_i[7]
    DIRECTION INPUT ;
    USE SIGNAL ;
    PORT
      LAYER met2 ;
        RECT 120.610 396.000 120.890 400.000 ;
    END
  END wbs_adr_i[7]
  PIN wbs_adr_i[8]
    DIRECTION INPUT ;
    USE SIGNAL ;
    PORT
      LAYER met2 ;
        RECT 131.650 396.000 131.930 400.000 ;
    END
  END wbs_adr_i[8]
  PIN wbs_adr_i[9]
    DIRECTION INPUT ;
    USE SIGNAL ;
    PORT
      LAYER met2 ;
        RECT 142.690 396.000 142.970 400.000 ;
    END
  END wbs_adr_i[9]
  PIN wbs_cyc_i
    DIRECTION INPUT ;
    USE SIGNAL ;
    ANTENNAGATEAREA 0.213000 ;
    PORT
      LAYER met2 ;
        RECT 17.570 396.000 17.850 400.000 ;
    END
  END wbs_cyc_i
  PIN wbs_dat_i[0]
    DIRECTION INPUT ;
    USE SIGNAL ;
    ANTENNAGATEAREA 0.126000 ;
    PORT
      LAYER met2 ;
        RECT 32.290 396.000 32.570 400.000 ;
    END
  END wbs_dat_i[0]
  PIN wbs_dat_i[10]
    DIRECTION INPUT ;
    USE SIGNAL ;
    ANTENNAGATEAREA 0.126000 ;
    PORT
      LAYER met2 ;
        RECT 157.410 396.000 157.690 400.000 ;
    END
  END wbs_dat_i[10]
  PIN wbs_dat_i[11]
    DIRECTION INPUT ;
    USE SIGNAL ;
    ANTENNAGATEAREA 0.126000 ;
    PORT
      LAYER met2 ;
        RECT 168.450 396.000 168.730 400.000 ;
    END
  END wbs_dat_i[11]
  PIN wbs_dat_i[12]
    DIRECTION INPUT ;
    USE SIGNAL ;
    ANTENNAGATEAREA 0.126000 ;
    PORT
      LAYER met2 ;
        RECT 179.490 396.000 179.770 400.000 ;
    END
  END wbs_dat_i[12]
  PIN wbs_dat_i[13]
    DIRECTION INPUT ;
    USE SIGNAL ;
    ANTENNAGATEAREA 0.126000 ;
    PORT
      LAYER met2 ;
        RECT 190.530 396.000 190.810 400.000 ;
    END
  END wbs_dat_i[13]
  PIN wbs_dat_i[14]
    DIRECTION INPUT ;
    USE SIGNAL ;
    ANTENNAGATEAREA 0.126000 ;
    PORT
      LAYER met2 ;
        RECT 201.570 396.000 201.850 400.000 ;
    END
  END wbs_dat_i[14]
  PIN wbs_dat_i[15]
    DIRECTION INPUT ;
    USE SIGNAL ;
    ANTENNAGATEAREA 0.126000 ;
    PORT
      LAYER met2 ;
        RECT 212.610 396.000 212.890 400.000 ;
    END
  END wbs_dat_i[15]
  PIN wbs_dat_i[16]
    DIRECTION INPUT ;
    USE SIGNAL ;
    ANTENNAGATEAREA 0.126000 ;
    PORT
      LAYER met2 ;
        RECT 223.650 396.000 223.930 400.000 ;
    END
  END wbs_dat_i[16]
  PIN wbs_dat_i[17]
    DIRECTION INPUT ;
    USE SIGNAL ;
    ANTENNAGATEAREA 0.126000 ;
    PORT
      LAYER met2 ;
        RECT 234.690 396.000 234.970 400.000 ;
    END
  END wbs_dat_i[17]
  PIN wbs_dat_i[18]
    DIRECTION INPUT ;
    USE SIGNAL ;
    ANTENNAGATEAREA 0.126000 ;
    PORT
      LAYER met2 ;
        RECT 245.730 396.000 246.010 400.000 ;
    END
  END wbs_dat_i[18]
  PIN wbs_dat_i[19]
    DIRECTION INPUT ;
    USE SIGNAL ;
    ANTENNAGATEAREA 0.126000 ;
    PORT
      LAYER met2 ;
        RECT 256.770 396.000 257.050 400.000 ;
    END
  END wbs_dat_i[19]
  PIN wbs_dat_i[1]
    DIRECTION INPUT ;
    USE SIGNAL ;
    ANTENNAGATEAREA 0.126000 ;
    PORT
      LAYER met2 ;
        RECT 47.010 396.000 47.290 400.000 ;
    END
  END wbs_dat_i[1]
  PIN wbs_dat_i[20]
    DIRECTION INPUT ;
    USE SIGNAL ;
    ANTENNAGATEAREA 0.126000 ;
    PORT
      LAYER met2 ;
        RECT 267.810 396.000 268.090 400.000 ;
    END
  END wbs_dat_i[20]
  PIN wbs_dat_i[21]
    DIRECTION INPUT ;
    USE SIGNAL ;
    ANTENNAGATEAREA 0.126000 ;
    PORT
      LAYER met2 ;
        RECT 278.850 396.000 279.130 400.000 ;
    END
  END wbs_dat_i[21]
  PIN wbs_dat_i[22]
    DIRECTION INPUT ;
    USE SIGNAL ;
    ANTENNAGATEAREA 0.126000 ;
    PORT
      LAYER met2 ;
        RECT 289.890 396.000 290.170 400.000 ;
    END
  END wbs_dat_i[22]
  PIN wbs_dat_i[23]
    DIRECTION INPUT ;
    USE SIGNAL ;
    ANTENNAGATEAREA 0.126000 ;
    PORT
      LAYER met2 ;
        RECT 300.930 396.000 301.210 400.000 ;
    END
  END wbs_dat_i[23]
  PIN wbs_dat_i[24]
    DIRECTION INPUT ;
    USE SIGNAL ;
    ANTENNAGATEAREA 0.126000 ;
    PORT
      LAYER met2 ;
        RECT 311.970 396.000 312.250 400.000 ;
    END
  END wbs_dat_i[24]
  PIN wbs_dat_i[25]
    DIRECTION INPUT ;
    USE SIGNAL ;
    ANTENNAGATEAREA 0.126000 ;
    PORT
      LAYER met2 ;
        RECT 323.010 396.000 323.290 400.000 ;
    END
  END wbs_dat_i[25]
  PIN wbs_dat_i[26]
    DIRECTION INPUT ;
    USE SIGNAL ;
    ANTENNAGATEAREA 0.126000 ;
    PORT
      LAYER met2 ;
        RECT 334.050 396.000 334.330 400.000 ;
    END
  END wbs_dat_i[26]
  PIN wbs_dat_i[27]
    DIRECTION INPUT ;
    USE SIGNAL ;
    ANTENNAGATEAREA 0.126000 ;
    PORT
      LAYER met2 ;
        RECT 345.090 396.000 345.370 400.000 ;
    END
  END wbs_dat_i[27]
  PIN wbs_dat_i[28]
    DIRECTION INPUT ;
    USE SIGNAL ;
    ANTENNAGATEAREA 0.126000 ;
    PORT
      LAYER met2 ;
        RECT 356.130 396.000 356.410 400.000 ;
    END
  END wbs_dat_i[28]
  PIN wbs_dat_i[29]
    DIRECTION INPUT ;
    USE SIGNAL ;
    ANTENNAGATEAREA 0.126000 ;
    PORT
      LAYER met2 ;
        RECT 367.170 396.000 367.450 400.000 ;
    END
  END wbs_dat_i[29]
  PIN wbs_dat_i[2]
    DIRECTION INPUT ;
    USE SIGNAL ;
    ANTENNAGATEAREA 0.126000 ;
    PORT
      LAYER met2 ;
        RECT 61.730 396.000 62.010 400.000 ;
    END
  END wbs_dat_i[2]
  PIN wbs_dat_i[30]
    DIRECTION INPUT ;
    USE SIGNAL ;
    ANTENNAGATEAREA 0.126000 ;
    PORT
      LAYER met2 ;
        RECT 378.210 396.000 378.490 400.000 ;
    END
  END wbs_dat_i[30]
  PIN wbs_dat_i[31]
    DIRECTION INPUT ;
    USE SIGNAL ;
    ANTENNAGATEAREA 0.126000 ;
    PORT
      LAYER met2 ;
        RECT 389.250 396.000 389.530 400.000 ;
    END
  END wbs_dat_i[31]
  PIN wbs_dat_i[3]
    DIRECTION INPUT ;
    USE SIGNAL ;
    ANTENNAGATEAREA 0.126000 ;
    PORT
      LAYER met2 ;
        RECT 76.450 396.000 76.730 400.000 ;
    END
  END wbs_dat_i[3]
  PIN wbs_dat_i[4]
    DIRECTION INPUT ;
    USE SIGNAL ;
    ANTENNAGATEAREA 0.126000 ;
    PORT
      LAYER met2 ;
        RECT 91.170 396.000 91.450 400.000 ;
    END
  END wbs_dat_i[4]
  PIN wbs_dat_i[5]
    DIRECTION INPUT ;
    USE SIGNAL ;
    ANTENNAGATEAREA 0.126000 ;
    PORT
      LAYER met2 ;
        RECT 102.210 396.000 102.490 400.000 ;
    END
  END wbs_dat_i[5]
  PIN wbs_dat_i[6]
    DIRECTION INPUT ;
    USE SIGNAL ;
    ANTENNAGATEAREA 0.126000 ;
    PORT
      LAYER met2 ;
        RECT 113.250 396.000 113.530 400.000 ;
    END
  END wbs_dat_i[6]
  PIN wbs_dat_i[7]
    DIRECTION INPUT ;
    USE SIGNAL ;
    ANTENNAGATEAREA 0.126000 ;
    PORT
      LAYER met2 ;
        RECT 124.290 396.000 124.570 400.000 ;
    END
  END wbs_dat_i[7]
  PIN wbs_dat_i[8]
    DIRECTION INPUT ;
    USE SIGNAL ;
    ANTENNAGATEAREA 0.126000 ;
    PORT
      LAYER met2 ;
        RECT 135.330 396.000 135.610 400.000 ;
    END
  END wbs_dat_i[8]
  PIN wbs_dat_i[9]
    DIRECTION INPUT ;
    USE SIGNAL ;
    ANTENNAGATEAREA 0.126000 ;
    PORT
      LAYER met2 ;
        RECT 146.370 396.000 146.650 400.000 ;
    END
  END wbs_dat_i[9]
  PIN wbs_dat_o[0]
    DIRECTION OUTPUT ;
    USE SIGNAL ;
    ANTENNADIFFAREA 2.673000 ;
    PORT
      LAYER met2 ;
        RECT 35.970 396.000 36.250 400.000 ;
    END
  END wbs_dat_o[0]
  PIN wbs_dat_o[10]
    DIRECTION OUTPUT ;
    USE SIGNAL ;
    ANTENNADIFFAREA 2.673000 ;
    PORT
      LAYER met2 ;
        RECT 161.090 396.000 161.370 400.000 ;
    END
  END wbs_dat_o[10]
  PIN wbs_dat_o[11]
    DIRECTION OUTPUT ;
    USE SIGNAL ;
    ANTENNADIFFAREA 2.673000 ;
    PORT
      LAYER met2 ;
        RECT 172.130 396.000 172.410 400.000 ;
    END
  END wbs_dat_o[11]
  PIN wbs_dat_o[12]
    DIRECTION OUTPUT ;
    USE SIGNAL ;
    ANTENNADIFFAREA 2.673000 ;
    PORT
      LAYER met2 ;
        RECT 183.170 396.000 183.450 400.000 ;
    END
  END wbs_dat_o[12]
  PIN wbs_dat_o[13]
    DIRECTION OUTPUT ;
    USE SIGNAL ;
    ANTENNADIFFAREA 2.673000 ;
    PORT
      LAYER met2 ;
        RECT 194.210 396.000 194.490 400.000 ;
    END
  END wbs_dat_o[13]
  PIN wbs_dat_o[14]
    DIRECTION OUTPUT ;
    USE SIGNAL ;
    ANTENNADIFFAREA 2.673000 ;
    PORT
      LAYER met2 ;
        RECT 205.250 396.000 205.530 400.000 ;
    END
  END wbs_dat_o[14]
  PIN wbs_dat_o[15]
    DIRECTION OUTPUT ;
    USE SIGNAL ;
    ANTENNADIFFAREA 2.673000 ;
    PORT
      LAYER met2 ;
        RECT 216.290 396.000 216.570 400.000 ;
    END
  END wbs_dat_o[15]
  PIN wbs_dat_o[16]
    DIRECTION OUTPUT ;
    USE SIGNAL ;
    ANTENNADIFFAREA 2.673000 ;
    PORT
      LAYER met2 ;
        RECT 227.330 396.000 227.610 400.000 ;
    END
  END wbs_dat_o[16]
  PIN wbs_dat_o[17]
    DIRECTION OUTPUT ;
    USE SIGNAL ;
    ANTENNADIFFAREA 2.673000 ;
    PORT
      LAYER met2 ;
        RECT 238.370 396.000 238.650 400.000 ;
    END
  END wbs_dat_o[17]
  PIN wbs_dat_o[18]
    DIRECTION OUTPUT ;
    USE SIGNAL ;
    ANTENNADIFFAREA 2.673000 ;
    PORT
      LAYER met2 ;
        RECT 249.410 396.000 249.690 400.000 ;
    END
  END wbs_dat_o[18]
  PIN wbs_dat_o[19]
    DIRECTION OUTPUT ;
    USE SIGNAL ;
    ANTENNADIFFAREA 2.673000 ;
    PORT
      LAYER met2 ;
        RECT 260.450 396.000 260.730 400.000 ;
    END
  END wbs_dat_o[19]
  PIN wbs_dat_o[1]
    DIRECTION OUTPUT ;
    USE SIGNAL ;
    ANTENNADIFFAREA 2.673000 ;
    PORT
      LAYER met2 ;
        RECT 50.690 396.000 50.970 400.000 ;
    END
  END wbs_dat_o[1]
  PIN wbs_dat_o[20]
    DIRECTION OUTPUT ;
    USE SIGNAL ;
    ANTENNADIFFAREA 2.673000 ;
    PORT
      LAYER met2 ;
        RECT 271.490 396.000 271.770 400.000 ;
    END
  END wbs_dat_o[20]
  PIN wbs_dat_o[21]
    DIRECTION OUTPUT ;
    USE SIGNAL ;
    ANTENNADIFFAREA 2.673000 ;
    PORT
      LAYER met2 ;
        RECT 282.530 396.000 282.810 400.000 ;
    END
  END wbs_dat_o[21]
  PIN wbs_dat_o[22]
    DIRECTION OUTPUT ;
    USE SIGNAL ;
    ANTENNADIFFAREA 2.673000 ;
    PORT
      LAYER met2 ;
        RECT 293.570 396.000 293.850 400.000 ;
    END
  END wbs_dat_o[22]
  PIN wbs_dat_o[23]
    DIRECTION OUTPUT ;
    USE SIGNAL ;
    ANTENNADIFFAREA 2.673000 ;
    PORT
      LAYER met2 ;
        RECT 304.610 396.000 304.890 400.000 ;
    END
  END wbs_dat_o[23]
  PIN wbs_dat_o[24]
    DIRECTION OUTPUT ;
    USE SIGNAL ;
    ANTENNADIFFAREA 2.673000 ;
    PORT
      LAYER met2 ;
        RECT 315.650 396.000 315.930 400.000 ;
    END
  END wbs_dat_o[24]
  PIN wbs_dat_o[25]
    DIRECTION OUTPUT ;
    USE SIGNAL ;
    ANTENNADIFFAREA 2.673000 ;
    PORT
      LAYER met2 ;
        RECT 326.690 396.000 326.970 400.000 ;
    END
  END wbs_dat_o[25]
  PIN wbs_dat_o[26]
    DIRECTION OUTPUT ;
    USE SIGNAL ;
    ANTENNADIFFAREA 2.673000 ;
    PORT
      LAYER met2 ;
        RECT 337.730 396.000 338.010 400.000 ;
    END
  END wbs_dat_o[26]
  PIN wbs_dat_o[27]
    DIRECTION OUTPUT ;
    USE SIGNAL ;
    ANTENNADIFFAREA 2.673000 ;
    PORT
      LAYER met2 ;
        RECT 348.770 396.000 349.050 400.000 ;
    END
  END wbs_dat_o[27]
  PIN wbs_dat_o[28]
    DIRECTION OUTPUT ;
    USE SIGNAL ;
    ANTENNADIFFAREA 2.673000 ;
    PORT
      LAYER met2 ;
        RECT 359.810 396.000 360.090 400.000 ;
    END
  END wbs_dat_o[28]
  PIN wbs_dat_o[29]
    DIRECTION OUTPUT ;
    USE SIGNAL ;
    ANTENNADIFFAREA 2.673000 ;
    PORT
      LAYER met2 ;
        RECT 370.850 396.000 371.130 400.000 ;
    END
  END wbs_dat_o[29]
  PIN wbs_dat_o[2]
    DIRECTION OUTPUT ;
    USE SIGNAL ;
    ANTENNADIFFAREA 2.673000 ;
    PORT
      LAYER met2 ;
        RECT 65.410 396.000 65.690 400.000 ;
    END
  END wbs_dat_o[2]
  PIN wbs_dat_o[30]
    DIRECTION OUTPUT ;
    USE SIGNAL ;
    ANTENNADIFFAREA 2.673000 ;
    PORT
      LAYER met2 ;
        RECT 381.890 396.000 382.170 400.000 ;
    END
  END wbs_dat_o[30]
  PIN wbs_dat_o[31]
    DIRECTION OUTPUT ;
    USE SIGNAL ;
    ANTENNADIFFAREA 2.673000 ;
    PORT
      LAYER met2 ;
        RECT 392.930 396.000 393.210 400.000 ;
    END
  END wbs_dat_o[31]
  PIN wbs_dat_o[3]
    DIRECTION OUTPUT ;
    USE SIGNAL ;
    ANTENNADIFFAREA 2.673000 ;
    PORT
      LAYER met2 ;
        RECT 80.130 396.000 80.410 400.000 ;
    END
  END wbs_dat_o[3]
  PIN wbs_dat_o[4]
    DIRECTION OUTPUT ;
    USE SIGNAL ;
    ANTENNADIFFAREA 2.673000 ;
    PORT
      LAYER met2 ;
        RECT 94.850 396.000 95.130 400.000 ;
    END
  END wbs_dat_o[4]
  PIN wbs_dat_o[5]
    DIRECTION OUTPUT ;
    USE SIGNAL ;
    ANTENNADIFFAREA 2.673000 ;
    PORT
      LAYER met2 ;
        RECT 105.890 396.000 106.170 400.000 ;
    END
  END wbs_dat_o[5]
  PIN wbs_dat_o[6]
    DIRECTION OUTPUT ;
    USE SIGNAL ;
    ANTENNADIFFAREA 2.673000 ;
    PORT
      LAYER met2 ;
        RECT 116.930 396.000 117.210 400.000 ;
    END
  END wbs_dat_o[6]
  PIN wbs_dat_o[7]
    DIRECTION OUTPUT ;
    USE SIGNAL ;
    ANTENNADIFFAREA 2.673000 ;
    PORT
      LAYER met2 ;
        RECT 127.970 396.000 128.250 400.000 ;
    END
  END wbs_dat_o[7]
  PIN wbs_dat_o[8]
    DIRECTION OUTPUT ;
    USE SIGNAL ;
    ANTENNADIFFAREA 2.673000 ;
    PORT
      LAYER met2 ;
        RECT 139.010 396.000 139.290 400.000 ;
    END
  END wbs_dat_o[8]
  PIN wbs_dat_o[9]
    DIRECTION OUTPUT ;
    USE SIGNAL ;
    ANTENNADIFFAREA 2.673000 ;
    PORT
      LAYER met2 ;
        RECT 150.050 396.000 150.330 400.000 ;
    END
  END wbs_dat_o[9]
  PIN wbs_sel_i[0]
    DIRECTION INPUT ;
    USE SIGNAL ;
    PORT
      LAYER met2 ;
        RECT 39.650 396.000 39.930 400.000 ;
    END
  END wbs_sel_i[0]
  PIN wbs_sel_i[1]
    DIRECTION INPUT ;
    USE SIGNAL ;
    PORT
      LAYER met2 ;
        RECT 54.370 396.000 54.650 400.000 ;
    END
  END wbs_sel_i[1]
  PIN wbs_sel_i[2]
    DIRECTION INPUT ;
    USE SIGNAL ;
    PORT
      LAYER met2 ;
        RECT 69.090 396.000 69.370 400.000 ;
    END
  END wbs_sel_i[2]
  PIN wbs_sel_i[3]
    DIRECTION INPUT ;
    USE SIGNAL ;
    PORT
      LAYER met2 ;
        RECT 83.810 396.000 84.090 400.000 ;
    END
  END wbs_sel_i[3]
  PIN wbs_stb_i
    DIRECTION INPUT ;
    USE SIGNAL ;
    ANTENNAGATEAREA 0.213000 ;
    PORT
      LAYER met2 ;
        RECT 21.250 396.000 21.530 400.000 ;
    END
  END wbs_stb_i
  PIN wbs_we_i
    DIRECTION INPUT ;
    USE SIGNAL ;
    ANTENNAGATEAREA 0.213000 ;
    PORT
      LAYER met2 ;
        RECT 24.930 396.000 25.210 400.000 ;
    END
  END wbs_we_i
  OBS
      LAYER nwell ;
        RECT 5.330 10.760 394.410 389.150 ;
      LAYER li1 ;
        RECT 5.520 10.795 394.220 389.045 ;
      LAYER met1 ;
        RECT 5.520 9.220 395.530 389.200 ;
      LAYER met2 ;
        RECT 7.090 395.720 9.930 396.170 ;
        RECT 10.770 395.720 13.610 396.170 ;
        RECT 14.450 395.720 17.290 396.170 ;
        RECT 18.130 395.720 20.970 396.170 ;
        RECT 21.810 395.720 24.650 396.170 ;
        RECT 25.490 395.720 28.330 396.170 ;
        RECT 29.170 395.720 32.010 396.170 ;
        RECT 32.850 395.720 35.690 396.170 ;
        RECT 36.530 395.720 39.370 396.170 ;
        RECT 40.210 395.720 43.050 396.170 ;
        RECT 43.890 395.720 46.730 396.170 ;
        RECT 47.570 395.720 50.410 396.170 ;
        RECT 51.250 395.720 54.090 396.170 ;
        RECT 54.930 395.720 57.770 396.170 ;
        RECT 58.610 395.720 61.450 396.170 ;
        RECT 62.290 395.720 65.130 396.170 ;
        RECT 65.970 395.720 68.810 396.170 ;
        RECT 69.650 395.720 72.490 396.170 ;
        RECT 73.330 395.720 76.170 396.170 ;
        RECT 77.010 395.720 79.850 396.170 ;
        RECT 80.690 395.720 83.530 396.170 ;
        RECT 84.370 395.720 87.210 396.170 ;
        RECT 88.050 395.720 90.890 396.170 ;
        RECT 91.730 395.720 94.570 396.170 ;
        RECT 95.410 395.720 98.250 396.170 ;
        RECT 99.090 395.720 101.930 396.170 ;
        RECT 102.770 395.720 105.610 396.170 ;
        RECT 106.450 395.720 109.290 396.170 ;
        RECT 110.130 395.720 112.970 396.170 ;
        RECT 113.810 395.720 116.650 396.170 ;
        RECT 117.490 395.720 120.330 396.170 ;
        RECT 121.170 395.720 124.010 396.170 ;
        RECT 124.850 395.720 127.690 396.170 ;
        RECT 128.530 395.720 131.370 396.170 ;
        RECT 132.210 395.720 135.050 396.170 ;
        RECT 135.890 395.720 138.730 396.170 ;
        RECT 139.570 395.720 142.410 396.170 ;
        RECT 143.250 395.720 146.090 396.170 ;
        RECT 146.930 395.720 149.770 396.170 ;
        RECT 150.610 395.720 153.450 396.170 ;
        RECT 154.290 395.720 157.130 396.170 ;
        RECT 157.970 395.720 160.810 396.170 ;
        RECT 161.650 395.720 164.490 396.170 ;
        RECT 165.330 395.720 168.170 396.170 ;
        RECT 169.010 395.720 171.850 396.170 ;
        RECT 172.690 395.720 175.530 396.170 ;
        RECT 176.370 395.720 179.210 396.170 ;
        RECT 180.050 395.720 182.890 396.170 ;
        RECT 183.730 395.720 186.570 396.170 ;
        RECT 187.410 395.720 190.250 396.170 ;
        RECT 191.090 395.720 193.930 396.170 ;
        RECT 194.770 395.720 197.610 396.170 ;
        RECT 198.450 395.720 201.290 396.170 ;
        RECT 202.130 395.720 204.970 396.170 ;
        RECT 205.810 395.720 208.650 396.170 ;
        RECT 209.490 395.720 212.330 396.170 ;
        RECT 213.170 395.720 216.010 396.170 ;
        RECT 216.850 395.720 219.690 396.170 ;
        RECT 220.530 395.720 223.370 396.170 ;
        RECT 224.210 395.720 227.050 396.170 ;
        RECT 227.890 395.720 230.730 396.170 ;
        RECT 231.570 395.720 234.410 396.170 ;
        RECT 235.250 395.720 238.090 396.170 ;
        RECT 238.930 395.720 241.770 396.170 ;
        RECT 242.610 395.720 245.450 396.170 ;
        RECT 246.290 395.720 249.130 396.170 ;
        RECT 249.970 395.720 252.810 396.170 ;
        RECT 253.650 395.720 256.490 396.170 ;
        RECT 257.330 395.720 260.170 396.170 ;
        RECT 261.010 395.720 263.850 396.170 ;
        RECT 264.690 395.720 267.530 396.170 ;
        RECT 268.370 395.720 271.210 396.170 ;
        RECT 272.050 395.720 274.890 396.170 ;
        RECT 275.730 395.720 278.570 396.170 ;
        RECT 279.410 395.720 282.250 396.170 ;
        RECT 283.090 395.720 285.930 396.170 ;
        RECT 286.770 395.720 289.610 396.170 ;
        RECT 290.450 395.720 293.290 396.170 ;
        RECT 294.130 395.720 296.970 396.170 ;
        RECT 297.810 395.720 300.650 396.170 ;
        RECT 301.490 395.720 304.330 396.170 ;
        RECT 305.170 395.720 308.010 396.170 ;
        RECT 308.850 395.720 311.690 396.170 ;
        RECT 312.530 395.720 315.370 396.170 ;
        RECT 316.210 395.720 319.050 396.170 ;
        RECT 319.890 395.720 322.730 396.170 ;
        RECT 323.570 395.720 326.410 396.170 ;
        RECT 327.250 395.720 330.090 396.170 ;
        RECT 330.930 395.720 333.770 396.170 ;
        RECT 334.610 395.720 337.450 396.170 ;
        RECT 338.290 395.720 341.130 396.170 ;
        RECT 341.970 395.720 344.810 396.170 ;
        RECT 345.650 395.720 348.490 396.170 ;
        RECT 349.330 395.720 352.170 396.170 ;
        RECT 353.010 395.720 355.850 396.170 ;
        RECT 356.690 395.720 359.530 396.170 ;
        RECT 360.370 395.720 363.210 396.170 ;
        RECT 364.050 395.720 366.890 396.170 ;
        RECT 367.730 395.720 370.570 396.170 ;
        RECT 371.410 395.720 374.250 396.170 ;
        RECT 375.090 395.720 377.930 396.170 ;
        RECT 378.770 395.720 381.610 396.170 ;
        RECT 382.450 395.720 385.290 396.170 ;
        RECT 386.130 395.720 388.970 396.170 ;
        RECT 389.810 395.720 392.650 396.170 ;
        RECT 393.490 395.720 395.510 396.170 ;
        RECT 6.540 4.280 395.510 395.720 ;
        RECT 6.540 4.000 17.290 4.280 ;
        RECT 18.130 4.000 47.650 4.280 ;
        RECT 48.490 4.000 78.010 4.280 ;
        RECT 78.850 4.000 108.370 4.280 ;
        RECT 109.210 4.000 138.730 4.280 ;
        RECT 139.570 4.000 169.090 4.280 ;
        RECT 169.930 4.000 199.450 4.280 ;
        RECT 200.290 4.000 229.810 4.280 ;
        RECT 230.650 4.000 260.170 4.280 ;
        RECT 261.010 4.000 290.530 4.280 ;
        RECT 291.370 4.000 320.890 4.280 ;
        RECT 321.730 4.000 351.250 4.280 ;
        RECT 352.090 4.000 381.610 4.280 ;
        RECT 382.450 4.000 395.510 4.280 ;
      LAYER met3 ;
        RECT 21.050 365.520 396.000 389.125 ;
        RECT 21.050 364.120 395.600 365.520 ;
        RECT 21.050 362.800 396.000 364.120 ;
        RECT 21.050 361.400 395.600 362.800 ;
        RECT 21.050 360.080 396.000 361.400 ;
        RECT 21.050 358.680 395.600 360.080 ;
        RECT 21.050 357.360 396.000 358.680 ;
        RECT 21.050 355.960 395.600 357.360 ;
        RECT 21.050 354.640 396.000 355.960 ;
        RECT 21.050 353.240 395.600 354.640 ;
        RECT 21.050 351.920 396.000 353.240 ;
        RECT 21.050 350.520 395.600 351.920 ;
        RECT 21.050 349.200 396.000 350.520 ;
        RECT 21.050 347.800 395.600 349.200 ;
        RECT 21.050 346.480 396.000 347.800 ;
        RECT 21.050 345.080 395.600 346.480 ;
        RECT 21.050 343.760 396.000 345.080 ;
        RECT 21.050 342.360 395.600 343.760 ;
        RECT 21.050 341.040 396.000 342.360 ;
        RECT 21.050 339.640 395.600 341.040 ;
        RECT 21.050 338.320 396.000 339.640 ;
        RECT 21.050 336.920 395.600 338.320 ;
        RECT 21.050 335.600 396.000 336.920 ;
        RECT 21.050 334.200 395.600 335.600 ;
        RECT 21.050 332.880 396.000 334.200 ;
        RECT 21.050 331.480 395.600 332.880 ;
        RECT 21.050 330.160 396.000 331.480 ;
        RECT 21.050 328.760 395.600 330.160 ;
        RECT 21.050 327.440 396.000 328.760 ;
        RECT 21.050 326.040 395.600 327.440 ;
        RECT 21.050 324.720 396.000 326.040 ;
        RECT 21.050 323.320 395.600 324.720 ;
        RECT 21.050 322.000 396.000 323.320 ;
        RECT 21.050 320.600 395.600 322.000 ;
        RECT 21.050 319.280 396.000 320.600 ;
        RECT 21.050 317.880 395.600 319.280 ;
        RECT 21.050 316.560 396.000 317.880 ;
        RECT 21.050 315.160 395.600 316.560 ;
        RECT 21.050 313.840 396.000 315.160 ;
        RECT 21.050 312.440 395.600 313.840 ;
        RECT 21.050 311.120 396.000 312.440 ;
        RECT 21.050 309.720 395.600 311.120 ;
        RECT 21.050 308.400 396.000 309.720 ;
        RECT 21.050 307.000 395.600 308.400 ;
        RECT 21.050 305.680 396.000 307.000 ;
        RECT 21.050 304.280 395.600 305.680 ;
        RECT 21.050 302.960 396.000 304.280 ;
        RECT 21.050 301.560 395.600 302.960 ;
        RECT 21.050 300.240 396.000 301.560 ;
        RECT 21.050 298.840 395.600 300.240 ;
        RECT 21.050 297.520 396.000 298.840 ;
        RECT 21.050 296.120 395.600 297.520 ;
        RECT 21.050 294.800 396.000 296.120 ;
        RECT 21.050 293.400 395.600 294.800 ;
        RECT 21.050 292.080 396.000 293.400 ;
        RECT 21.050 290.680 395.600 292.080 ;
        RECT 21.050 289.360 396.000 290.680 ;
        RECT 21.050 287.960 395.600 289.360 ;
        RECT 21.050 286.640 396.000 287.960 ;
        RECT 21.050 285.240 395.600 286.640 ;
        RECT 21.050 283.920 396.000 285.240 ;
        RECT 21.050 282.520 395.600 283.920 ;
        RECT 21.050 281.200 396.000 282.520 ;
        RECT 21.050 279.800 395.600 281.200 ;
        RECT 21.050 278.480 396.000 279.800 ;
        RECT 21.050 277.080 395.600 278.480 ;
        RECT 21.050 275.760 396.000 277.080 ;
        RECT 21.050 274.360 395.600 275.760 ;
        RECT 21.050 273.040 396.000 274.360 ;
        RECT 21.050 271.640 395.600 273.040 ;
        RECT 21.050 270.320 396.000 271.640 ;
        RECT 21.050 268.920 395.600 270.320 ;
        RECT 21.050 267.600 396.000 268.920 ;
        RECT 21.050 266.200 395.600 267.600 ;
        RECT 21.050 264.880 396.000 266.200 ;
        RECT 21.050 263.480 395.600 264.880 ;
        RECT 21.050 262.160 396.000 263.480 ;
        RECT 21.050 260.760 395.600 262.160 ;
        RECT 21.050 259.440 396.000 260.760 ;
        RECT 21.050 258.040 395.600 259.440 ;
        RECT 21.050 256.720 396.000 258.040 ;
        RECT 21.050 255.320 395.600 256.720 ;
        RECT 21.050 254.000 396.000 255.320 ;
        RECT 21.050 252.600 395.600 254.000 ;
        RECT 21.050 251.280 396.000 252.600 ;
        RECT 21.050 249.880 395.600 251.280 ;
        RECT 21.050 248.560 396.000 249.880 ;
        RECT 21.050 247.160 395.600 248.560 ;
        RECT 21.050 245.840 396.000 247.160 ;
        RECT 21.050 244.440 395.600 245.840 ;
        RECT 21.050 243.120 396.000 244.440 ;
        RECT 21.050 241.720 395.600 243.120 ;
        RECT 21.050 240.400 396.000 241.720 ;
        RECT 21.050 239.000 395.600 240.400 ;
        RECT 21.050 237.680 396.000 239.000 ;
        RECT 21.050 236.280 395.600 237.680 ;
        RECT 21.050 234.960 396.000 236.280 ;
        RECT 21.050 233.560 395.600 234.960 ;
        RECT 21.050 232.240 396.000 233.560 ;
        RECT 21.050 230.840 395.600 232.240 ;
        RECT 21.050 229.520 396.000 230.840 ;
        RECT 21.050 228.120 395.600 229.520 ;
        RECT 21.050 226.800 396.000 228.120 ;
        RECT 21.050 225.400 395.600 226.800 ;
        RECT 21.050 224.080 396.000 225.400 ;
        RECT 21.050 222.680 395.600 224.080 ;
        RECT 21.050 221.360 396.000 222.680 ;
        RECT 21.050 219.960 395.600 221.360 ;
        RECT 21.050 218.640 396.000 219.960 ;
        RECT 21.050 217.240 395.600 218.640 ;
        RECT 21.050 215.920 396.000 217.240 ;
        RECT 21.050 214.520 395.600 215.920 ;
        RECT 21.050 213.200 396.000 214.520 ;
        RECT 21.050 211.800 395.600 213.200 ;
        RECT 21.050 210.480 396.000 211.800 ;
        RECT 21.050 209.080 395.600 210.480 ;
        RECT 21.050 207.760 396.000 209.080 ;
        RECT 21.050 206.360 395.600 207.760 ;
        RECT 21.050 205.040 396.000 206.360 ;
        RECT 21.050 203.640 395.600 205.040 ;
        RECT 21.050 202.320 396.000 203.640 ;
        RECT 21.050 200.920 395.600 202.320 ;
        RECT 21.050 199.600 396.000 200.920 ;
        RECT 21.050 198.200 395.600 199.600 ;
        RECT 21.050 196.880 396.000 198.200 ;
        RECT 21.050 195.480 395.600 196.880 ;
        RECT 21.050 194.160 396.000 195.480 ;
        RECT 21.050 192.760 395.600 194.160 ;
        RECT 21.050 191.440 396.000 192.760 ;
        RECT 21.050 190.040 395.600 191.440 ;
        RECT 21.050 188.720 396.000 190.040 ;
        RECT 21.050 187.320 395.600 188.720 ;
        RECT 21.050 186.000 396.000 187.320 ;
        RECT 21.050 184.600 395.600 186.000 ;
        RECT 21.050 183.280 396.000 184.600 ;
        RECT 21.050 181.880 395.600 183.280 ;
        RECT 21.050 180.560 396.000 181.880 ;
        RECT 21.050 179.160 395.600 180.560 ;
        RECT 21.050 177.840 396.000 179.160 ;
        RECT 21.050 176.440 395.600 177.840 ;
        RECT 21.050 175.120 396.000 176.440 ;
        RECT 21.050 173.720 395.600 175.120 ;
        RECT 21.050 172.400 396.000 173.720 ;
        RECT 21.050 171.000 395.600 172.400 ;
        RECT 21.050 169.680 396.000 171.000 ;
        RECT 21.050 168.280 395.600 169.680 ;
        RECT 21.050 166.960 396.000 168.280 ;
        RECT 21.050 165.560 395.600 166.960 ;
        RECT 21.050 164.240 396.000 165.560 ;
        RECT 21.050 162.840 395.600 164.240 ;
        RECT 21.050 161.520 396.000 162.840 ;
        RECT 21.050 160.120 395.600 161.520 ;
        RECT 21.050 158.800 396.000 160.120 ;
        RECT 21.050 157.400 395.600 158.800 ;
        RECT 21.050 156.080 396.000 157.400 ;
        RECT 21.050 154.680 395.600 156.080 ;
        RECT 21.050 153.360 396.000 154.680 ;
        RECT 21.050 151.960 395.600 153.360 ;
        RECT 21.050 150.640 396.000 151.960 ;
        RECT 21.050 149.240 395.600 150.640 ;
        RECT 21.050 147.920 396.000 149.240 ;
        RECT 21.050 146.520 395.600 147.920 ;
        RECT 21.050 145.200 396.000 146.520 ;
        RECT 21.050 143.800 395.600 145.200 ;
        RECT 21.050 142.480 396.000 143.800 ;
        RECT 21.050 141.080 395.600 142.480 ;
        RECT 21.050 139.760 396.000 141.080 ;
        RECT 21.050 138.360 395.600 139.760 ;
        RECT 21.050 137.040 396.000 138.360 ;
        RECT 21.050 135.640 395.600 137.040 ;
        RECT 21.050 134.320 396.000 135.640 ;
        RECT 21.050 132.920 395.600 134.320 ;
        RECT 21.050 131.600 396.000 132.920 ;
        RECT 21.050 130.200 395.600 131.600 ;
        RECT 21.050 128.880 396.000 130.200 ;
        RECT 21.050 127.480 395.600 128.880 ;
        RECT 21.050 126.160 396.000 127.480 ;
        RECT 21.050 124.760 395.600 126.160 ;
        RECT 21.050 123.440 396.000 124.760 ;
        RECT 21.050 122.040 395.600 123.440 ;
        RECT 21.050 120.720 396.000 122.040 ;
        RECT 21.050 119.320 395.600 120.720 ;
        RECT 21.050 118.000 396.000 119.320 ;
        RECT 21.050 116.600 395.600 118.000 ;
        RECT 21.050 115.280 396.000 116.600 ;
        RECT 21.050 113.880 395.600 115.280 ;
        RECT 21.050 112.560 396.000 113.880 ;
        RECT 21.050 111.160 395.600 112.560 ;
        RECT 21.050 109.840 396.000 111.160 ;
        RECT 21.050 108.440 395.600 109.840 ;
        RECT 21.050 107.120 396.000 108.440 ;
        RECT 21.050 105.720 395.600 107.120 ;
        RECT 21.050 104.400 396.000 105.720 ;
        RECT 21.050 103.000 395.600 104.400 ;
        RECT 21.050 101.680 396.000 103.000 ;
        RECT 21.050 100.280 395.600 101.680 ;
        RECT 21.050 98.960 396.000 100.280 ;
        RECT 21.050 97.560 395.600 98.960 ;
        RECT 21.050 96.240 396.000 97.560 ;
        RECT 21.050 94.840 395.600 96.240 ;
        RECT 21.050 93.520 396.000 94.840 ;
        RECT 21.050 92.120 395.600 93.520 ;
        RECT 21.050 90.800 396.000 92.120 ;
        RECT 21.050 89.400 395.600 90.800 ;
        RECT 21.050 88.080 396.000 89.400 ;
        RECT 21.050 86.680 395.600 88.080 ;
        RECT 21.050 85.360 396.000 86.680 ;
        RECT 21.050 83.960 395.600 85.360 ;
        RECT 21.050 82.640 396.000 83.960 ;
        RECT 21.050 81.240 395.600 82.640 ;
        RECT 21.050 79.920 396.000 81.240 ;
        RECT 21.050 78.520 395.600 79.920 ;
        RECT 21.050 77.200 396.000 78.520 ;
        RECT 21.050 75.800 395.600 77.200 ;
        RECT 21.050 74.480 396.000 75.800 ;
        RECT 21.050 73.080 395.600 74.480 ;
        RECT 21.050 71.760 396.000 73.080 ;
        RECT 21.050 70.360 395.600 71.760 ;
        RECT 21.050 69.040 396.000 70.360 ;
        RECT 21.050 67.640 395.600 69.040 ;
        RECT 21.050 66.320 396.000 67.640 ;
        RECT 21.050 64.920 395.600 66.320 ;
        RECT 21.050 63.600 396.000 64.920 ;
        RECT 21.050 62.200 395.600 63.600 ;
        RECT 21.050 60.880 396.000 62.200 ;
        RECT 21.050 59.480 395.600 60.880 ;
        RECT 21.050 58.160 396.000 59.480 ;
        RECT 21.050 56.760 395.600 58.160 ;
        RECT 21.050 55.440 396.000 56.760 ;
        RECT 21.050 54.040 395.600 55.440 ;
        RECT 21.050 52.720 396.000 54.040 ;
        RECT 21.050 51.320 395.600 52.720 ;
        RECT 21.050 50.000 396.000 51.320 ;
        RECT 21.050 48.600 395.600 50.000 ;
        RECT 21.050 47.280 396.000 48.600 ;
        RECT 21.050 45.880 395.600 47.280 ;
        RECT 21.050 44.560 396.000 45.880 ;
        RECT 21.050 43.160 395.600 44.560 ;
        RECT 21.050 41.840 396.000 43.160 ;
        RECT 21.050 40.440 395.600 41.840 ;
        RECT 21.050 39.120 396.000 40.440 ;
        RECT 21.050 37.720 395.600 39.120 ;
        RECT 21.050 36.400 396.000 37.720 ;
        RECT 21.050 35.000 395.600 36.400 ;
        RECT 21.050 33.680 396.000 35.000 ;
        RECT 21.050 32.280 395.600 33.680 ;
        RECT 21.050 10.715 396.000 32.280 ;
      LAYER met4 ;
        RECT 183.375 93.335 327.840 386.745 ;
        RECT 330.240 93.335 331.140 386.745 ;
        RECT 333.540 93.335 386.105 386.745 ;
  END
END afe_wb
END LIBRARY

